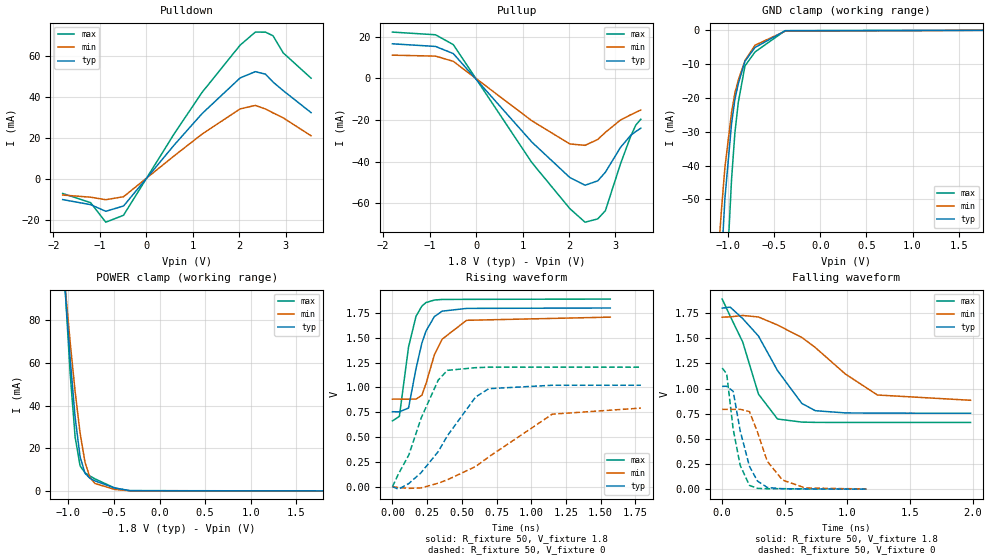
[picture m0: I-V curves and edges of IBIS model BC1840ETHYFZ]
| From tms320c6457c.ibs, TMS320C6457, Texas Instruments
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|   Model Cell BC1840ETHYFZ
[Model]   BC1840ETHYFZ
Model_type   I/O
Polarity   Non-Inverting
Enable   Active-Low
Vinl =  0.63
Vinh =  1.17
Cref =  15pF
Rref =  100.00M
Vref =  0V
Vmeas =  0.9
C_comp   1.349819p   1.120324p   1.692072p
[Model Spec]
Vinl   0.63   0.5985   0.6615
Vinh   1.17   1.1115   1.2285
[Temperature Range]   25   125   -40
[Voltage Range]   1.8   1.71   1.89
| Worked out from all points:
|   slope of the pulldown table from 0 to 0.27 V, typ, clamps not added: 35.3 ohm
|   slope of the pullup table from 0 to 0.27 V, typ, clamps not added: 37.2 ohm
|   GND clamp passes 1 mA (typ) near -0.49 V on its own axis
|   POWER clamp passes 1 mA (typ) near -0.46 V on its own axis
|   rising waveform, R_fixture 50, V_fixture 1.8: 20-80 % time 106ps typ, 144ps min, 82.5ps max; typ from 0.755 V to 1.8 V
|   rising waveform, R_fixture 50, V_fixture 0: 20-80 % time 301ps typ, 481ps min, 204ps max; typ from 0 V to 1.02 V
|   falling waveform, R_fixture 50, V_fixture 1.8: 20-80 % time 318ps typ, 511ps min, 210ps max; typ from 1.8 V to 0.755 V
|   falling waveform, R_fixture 50, V_fixture 0: 20-80 % time 111ps typ, 155ps min, 87.7ps max; typ from 1.02 V to 0.001 V
[POWER_clamp]
|   voltage   I(typ)   I(min)   I(max)
-1.8V     632.8mA    511.6mA    764.8mA
-1.055V   105.4mA    104.1mA    108.4mA
-1.036V   93.87mA    95.15mA    94.04mA
-981.8mV  61.86mA    69.76mA    55.16mA
-927.3mV  34.54mA    46.61mA    25.28mA
-872.7mV  15.98mA    27.11mA    11.74mA
-818.2mV  8.247mA    13.33mA    8.475mA
-763.6mV  5.887mA    6.222mA    6.958mA
-709.1mV  4.698mA    3.474mA    5.639mA
-490.9mV  1.354mA    698.9uA    1.342mA
-327.3mV  148.4uA    55.01uA    101.1uA
1.8V      1.91nA     90.78nA    1.181nA
[Pulldown]
|   voltage   I(typ)   I(min)   I(max)
-1.8V     -9.975mA   -7.741mA   -6.98mA
-1.2V     -12.44mA   -8.799mA   -11.46mA
-872.7mV  -15.69mA   -10.03mA   -21.01mA
-490.9mV  -13.1mA    -8.569mA   -17.62mA
600mV     16.72mA    11.42mA    22.21mA
1.2V      32.04mA    22.03mA    42.42mA
2.018V    49.45mA    34.33mA    65.47mA
2.345V    52.52mA    36.03mA    71.85mA
2.564V    51.3mA     34.29mA    71.83mA
2.727V    47.43mA    32.37mA    70.04mA
2.945V    43.27mA    29.96mA    61.7mA
3.545V    32.51mA    21.19mA    49.34mA
[Pullup]
|   voltage   I(typ)   I(min)   I(max)
-1.8V     16.61mA    11.16mA    22.24mA
-872.7mV  15.35mA    10.7mA     20.95mA
-490.9mV  11.93mA    8.207mA    16.23mA
1.2V      -30.58mA   -20.35mA   -40.43mA
2.018V    -47.62mA   -31.49mA   -62.56mA
2.345V    -51.31mA   -32.14mA   -69.06mA
2.618V    -49.2mA    -29.35mA   -67.48mA
2.782V    -45.08mA   -25.92mA   -63.56mA
3.109V    -33.1mA    -19.97mA   -40.96mA
3.327V    -27.37mA   -17.47mA   -27.8mA
3.436V    -25.53mA   -16.32mA   -22.48mA
3.545V    -23.89mA   -15.19mA   -19.61mA
[GND_clamp]
|   voltage   I(typ)   I(min)   I(max)
-1.8V     -625.6mA   -431.7mA   -991.9mA
-1.145V   -111.9mA   -81.73mA   -187.7mA
-1.109V   -89.09mA   -66.77mA   -149.9mA
-1.073V   -68.4mA    -53.08mA   -115.1mA
-1.036V   -49.81mA   -40.66mA   -83.47mA
-963.6mV  -27.57mA   -24.26mA   -44.03mA
-927.3mV  -20.4mA    -18.51mA   -30.3mA
-890.9mV  -15.83mA   -14.79mA   -21.39mA
-818.2mV  -9.128mA   -8.959mA   -10.52mA
-709.1mV  -5.065mA   -4.407mA   -6.394mA
-381.8mV  -133.5uA   -250.9uA   -83.03uA
1.764V    525.5pA    131nA      211pA
[Ramp]
| variable   typ   min   max
dV/dt_f  0.6424274/0.3293562n   0.509031/0.5327809n  0.7545297/0.2171174n
dV/dt_r  0.6288352/0.3128308n  0.4883315/0.5013298n  0.7405774/0.21202n
R_load = 50
[Rising Waveform]
R_fixture = 50
V_fixture = 1.8
V_fixture_min = 1.71
V_fixture_max = 1.89
|   time   V(typ)   V(min)   V(max)
0s        755.2mV    882.1mV    663.1mV
50ps      754.3mV    882.1mV    708.2mV
116ps     792.6mV    881.9mV    1.407V
170ps     1.19V      882.6mV    1.717V
212ps     1.446V     921.1mV    1.819V
242ps     1.568V     1.039V     1.855V
302ps     1.713V     1.327V     1.88V
358ps     1.768V     1.486V     1.886V
534ps     1.796V     1.676V     1.887V
1.57ns    1.8V       1.708V     1.89V
[Rising Waveform]
R_fixture = 50
V_fixture = 0
V_fixture_min = 0
V_fixture_max = 0
|   time   V(typ)   V(min)   V(max)
0s        88.36nV    176nV      31.28nV
44ps      -24.59mV   -7.139mV   130.6mV
118ps     31.98mV    -16.45mV   320mV
206ps     140.5mV    -11.95mV   688.5mV
330ps     353.8mV    35.61mV    1.074V
396ps     513.4mV    69.67mV    1.172V
600ps     904.5mV    203.8mV    1.199V
694ps     987.5mV    300.5mV    1.204V
1.152ns   1.022V     730.9mV    1.204V
1.79ns    1.022V     791.8mV    1.204V
[Falling Waveform]
R_fixture = 50
V_fixture = 1.8
V_fixture_min = 1.71
V_fixture_max = 1.89
|   time   V(typ)   V(min)   V(max)
0s        1.8V       1.71V      1.89V
64ps      1.81V      1.713V     1.72V
164ps     1.696V     1.727V     1.463V
290ps     1.522V     1.712V     944.6mV
442ps     1.179V     1.632V     697.4mV
636ps     852.7mV    1.508V     666.9mV
744ps     780mV      1.408V     664mV
984ps     758.2mV    1.145V     663.2mV
1.24ns    755.6mV    936.2mV    663.1mV
1.984ns   755.2mV    883.8mV    663.1mV
[Falling Waveform]
R_fixture = 50
V_fixture = 0
V_fixture_min = 0
V_fixture_max = 0
|   time   V(typ)   V(min)   V(max)
0s        1.022V     793.5mV    1.204V
36ps      1.023V     793.5mV    1.147V
88ps      972.3mV    793.5mV    594.9mV
144ps     579.8mV    794mV      236.3mV
218ps     226.5mV    771.5mV    37.12mV
282ps     80.7mV     568.1mV    7.818mV
360ps     17.06mV    277.6mV    4.059mV
482ps     3.902mV    90.58mV    4.92mV
664ps     2.308mV    12.01mV    2.412mV
1.152ns   1.265mV    1.72mV     56.76uV
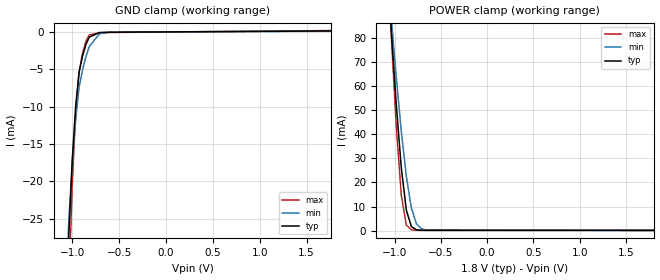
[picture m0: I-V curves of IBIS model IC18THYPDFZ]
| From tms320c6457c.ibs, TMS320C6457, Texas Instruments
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|   Model Cell IC18THYPDFZ
[Model]   IC18THYPDFZ
Model_type   Input
Polarity   Non-Inverting
|Cell operated at 1.8(nom)
|BUFFER OPERATING IN WEAK PULLDOWN MODE
|WITH +/- 5% VDDS
Vinl =  0.63
Vinh =  1.17
C_comp   0.7118224p   0.6228336p   0.8322228p
[Model Spec]
Vinl   0.63   0.5985   0.6615
Vinh   1.17   1.1115   1.2285
[Temperature Range]   25   125   -40
[Voltage Range]   1.8   1.71   1.89
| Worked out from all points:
|   GND clamp passes 1 mA (typ) near -0.83 V on its own axis
|   POWER clamp passes 1 mA (typ) near -0.79 V on its own axis
[POWER_clamp]
|   voltage   I(typ)   I(min)   I(max)
-1.8V     607.1mA    492.9mA    733.7mA
-1.055V   94.83mA    97.26mA    95.27mA
-1.036V   83.65mA    88.56mA    81.36mA
-981.8mV  52.59mA    63.87mA    43.61mA
-927.3mV  26.18mA    41.38mA    14.77mA
-872.7mV  8.488mA    22.52mA    2.281mA
-818.2mV  1.679mA    9.367mA    329.5uA
-763.6mV  320.4uA    2.879mA    161.9uA
-709.1mV  122uA      754.7uA    149.4uA
-654.5mV  95.78uA    214.5uA    148.3uA
1.8V      90.13uA    54.48uA    145.3uA
[GND_clamp]
|   voltage   I(typ)   I(min)   I(max)
-1.8V     -542mA     -381.8mA   -757.7mA
-1.073V   -42.86mA   -36.02mA   -57.35mA
-1.036V   -26.92mA   -25.12mA   -33.88mA
-1V       -17.11mA   -17.6mA    -20.43mA
-963.6mV  -9.945mA   -11.71mA   -10.93mA
-927.3mV  -5.429mA   -7.442mA   -5.388mA
-890.9mV  -3.287mA   -5.15mA    -2.922mA
-854.5mV  -1.723mA   -3.324mA   -1.27mA
-818.2mV  -734.7uA   -1.966mA   -430.8uA
-709.1mV  -120uA     -294.3uA   -144.9uA
-600mV    -81.62uA   -67.48uA   -118.2uA
1.764V    90uA       54.59uA    144.6uA
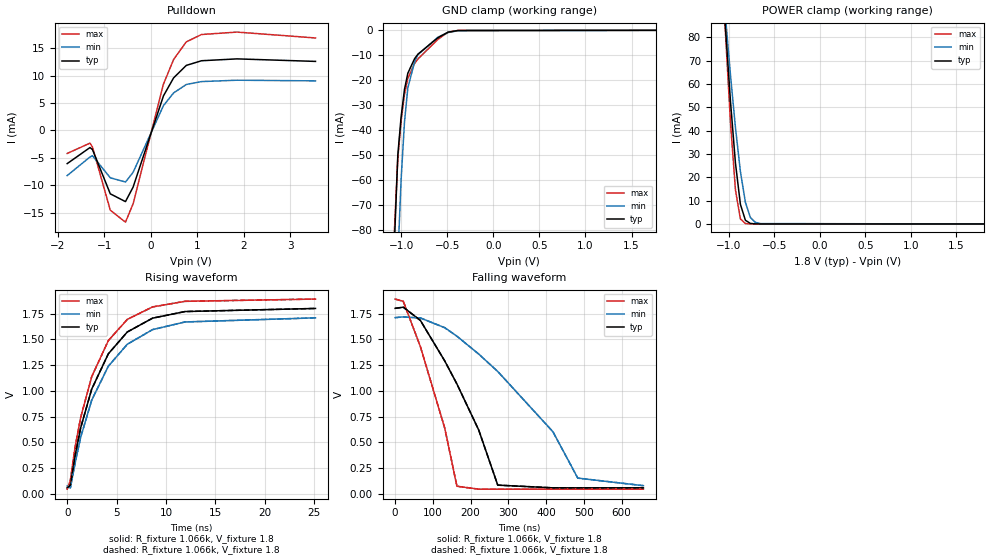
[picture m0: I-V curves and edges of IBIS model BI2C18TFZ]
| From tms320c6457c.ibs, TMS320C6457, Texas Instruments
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|   Model Cell BI2C18TFZ
|BI2C18TFZ_1P8
[Model]   BI2C18TFZ
Model_type   I/O_open_drain
Polarity   Non-Inverting
Enable   Active-Low
|Cell operated at 1.8(nom)
|BUFFER WITH +/- 5% VDDS
Vinl =  0.54
Vinh =  1.26
Cref =  400pF
Rref =  528
Vref =  1.8V
Vmeas =  0.9
C_comp   2.200517p   2.105009p   2.204653p
[Model Spec]
Vinl   0.54   0.513   0.567
Vinh   1.26   1.197   1.323
[Temperature Range]   25   125   -40
[Voltage Range]   1.8   1.71   1.89
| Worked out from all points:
|   slope of the pulldown table from 0 to 0.27 V, typ, clamps not added: 43.2 ohm
|   GND clamp passes 1 mA (typ) near -0.51 V on its own axis
|   POWER clamp passes 1 mA (typ) near -0.79 V on its own axis
|   rising waveform, R_fixture 1.066k, V_fixture 1.8: 20-80 % time 3.98ns typ, 4.3ns min, 3.66ns max; typ from 0.06 V to 1.8 V
|   rising waveform, R_fixture 1.066k, V_fixture 1.8: 20-80 % time 3.98ns typ, 4.3ns min, 3.66ns max; typ from 0.06 V to 1.8 V
|   falling waveform, R_fixture 1.066k, V_fixture 1.8: 20-80 % time 134ns typ, 236ns min, 86.2ns max; typ from 1.8 V to 0.06 V
|   falling waveform, R_fixture 1.066k, V_fixture 1.8: 20-80 % time 134ns typ, 236ns min, 86.2ns max; typ from 1.8 V to 0.06 V
[POWER_clamp]
|   voltage   I(typ)   I(min)   I(max)
-1.8V     607mA      492.8mA    733.6mA
-1.055V   94.75mA    97.21mA    95.13mA
-1.036V   83.56mA    88.51mA    81.22mA
-981.8mV  52.51mA    63.81mA    43.47mA
-927.3mV  26.09mA    41.33mA    14.63mA
-872.7mV  8.398mA    22.47mA    2.133mA
-818.2mV  1.587mA    9.312mA    180.9uA
-763.6mV  228.3uA    2.824mA    13.44uA
-709.1mV  29.99uA    699.2uA    1.06uA
-654.5mV  3.859uA    159uA      146.5nA
1.8V      1.028nA    44.53nA    569.6pA
[Pulldown]
|   voltage   I(typ)   I(min)   I(max)
-1.8V     -6.04mA    -8.214mA   -4.186mA
-1.309V   -3.11mA    -4.831mA   -2.309mA
-1.255V   -3.493mA   -4.611mA   -3.032mA
-872.7mV  -11.54mA   -8.621mA   -14.52mA
-545.5mV  -12.96mA   -9.39mA    -16.71mA
-381.8mV  -10.33mA   -7.634mA   -13.37mA
272.7mV   6.31mA     4.531mA    8.464mA
490.9mV   9.582mA    6.839mA    12.93mA
763.6mV   11.85mA    8.375mA    16.14mA
1.091V    12.7mA     8.903mA    17.48mA
1.855V    13.04mA    9.156mA    17.92mA
3.545V    12.58mA    9.032mA    16.85mA
[GND_clamp]
|   voltage   I(typ)   I(min)   I(max)
-1.8V     -4.55A     -4.415A    -4.715A
-1.073V   -85.44mA   -159.9mA   -80.66mA
-1.036V   -50.11mA   -91.94mA   -51.37mA
-1V       -34.68mA   -59.8mA    -36.45mA
-963.6mV  -23.72mA   -36.86mA   -25.76mA
-927.3mV  -17.22mA   -23.12mA   -19.3mA
-854.5mV  -11.44mA   -12.73mA   -13.33mA
-818.2mV  -9.595mA   -9.796mA   -11.52mA
-600mV    -2.95mA    -2.738mA   -3.602mA
-490.9mV  -739.5uA   -891.5uA   -763.3uA
-381.8mV  -69.49uA   -145.4uA   -41.6uA
1.764V    959.8pA    46.51nA    169.7pA
[Ramp]
| variable   typ   min   max
dV/dt_f   1.051879/0.1358345u  0.9823889/0.2380683u   1.118592/87.62096n
dV/dt_r  0.1590767/0.3489175n   0.121841/0.5578951n  0.1864863/0.251782n
R_load = 1.066k
[Rising Waveform]
R_fixture = 1.066k
V_fixture = 1.8
V_fixture_min = 1.71
V_fixture_max = 1.89
|   time   V(typ)   V(min)   V(max)
0s        60.28mV    79.47mV    47.35mV
320ps     83.48mV    60.28mV    131.3mV
800ps     373mV      299.4mV    455.6mV
1.36ns    640.9mV    549.7mV    740.3mV
2.48ns    1.017V     910.1mV    1.138V
4.16ns    1.359V     1.239V     1.487V
6.08ns    1.571V     1.452V     1.693V
8.64ns    1.705V     1.594V     1.814V
11.92ns   1.769V     1.668V     1.868V
25.12ns   1.799V     1.708V     1.89V
[Rising Waveform]
R_fixture = 1.066k
V_fixture = 1.8
V_fixture_min = 1.71
V_fixture_max = 1.89
|   time   V(typ)   V(min)   V(max)
0s        60.28mV    79.47mV    47.35mV
320ps     83.48mV    60.28mV    131.3mV
800ps     373mV      299.4mV    455.6mV
1.36ns    640.9mV    549.7mV    740.3mV
2.48ns    1.017V     910.1mV    1.138V
4.16ns    1.359V     1.239V     1.487V
6.08ns    1.571V     1.452V     1.693V
8.64ns    1.705V     1.594V     1.814V
11.92ns   1.769V     1.668V     1.868V
25.12ns   1.799V     1.708V     1.89V
[Falling Waveform]
R_fixture = 1.066k
V_fixture = 1.8
V_fixture_min = 1.71
V_fixture_max = 1.89
|   time   V(typ)   V(min)   V(max)
0s        1.8V       1.71V      1.89V
21.68ns   1.811V     1.717V     1.868V
66.96ns   1.683V     1.707V     1.429V
131.7ns   1.289V     1.612V     636.7mV
163.8ns   1.067V     1.53V      75.51mV
221.5ns   621.3mV    1.357V     47.7mV
272ns     86.4mV     1.188V     47.36mV
418.1ns   60.32mV    604.4mV    47.35mV
484.1ns   60.28mV    154.5mV    47.35mV
658ns     60.28mV    81.19mV    47.35mV
[Falling Waveform]
R_fixture = 1.066k
V_fixture = 1.8
V_fixture_min = 1.71
V_fixture_max = 1.89
|   time   V(typ)   V(min)   V(max)
0s        1.8V       1.71V      1.89V
21.68ns   1.811V     1.717V     1.868V
66.96ns   1.683V     1.707V     1.429V
131.7ns   1.289V     1.612V     636.7mV
163.8ns   1.067V     1.53V      75.51mV
221.5ns   621.3mV    1.357V     47.7mV
272ns     86.4mV     1.188V     47.36mV
418.1ns   60.32mV    604.4mV    47.35mV
484.1ns   60.28mV    154.5mV    47.35mV
658ns     60.28mV    81.19mV    47.35mV
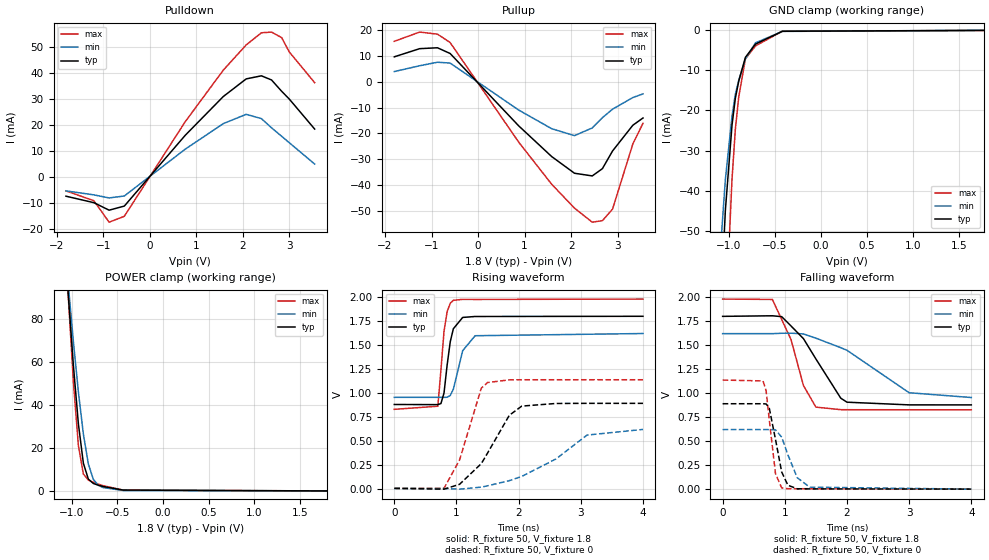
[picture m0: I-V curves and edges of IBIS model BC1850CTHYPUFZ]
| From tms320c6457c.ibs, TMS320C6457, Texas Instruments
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|   Model Cell BC1850CTHYPUFZ
[Model]   BC1850CTHYPUFZ
Model_type   I/O
Polarity   Non-Inverting
Enable   Active-Low
|Cell operated at 1.8(nom) PULLUP_ON
Vinl =  0.63
Vinh =  1.17
Cref =  15.0000pF
Rref =  100.0000M
Vref =  0V
Vmeas =  0.9
C_comp   1.238561p   1.006605p   1.548795p
[Model Spec]
Vinl   0.63   0.567   0.693
Vinh   1.17   1.053   1.287
[Temperature Range]   25   125   -40
[Voltage Range]   1.8   1.62   1.98
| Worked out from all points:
|   slope of the pulldown table from 0 to 0.27 V, typ, clamps not added: 45.7 ohm
|   slope of the pullup table from 0 to 0.27 V, typ, clamps not added: 49.4 ohm
|   GND clamp passes 1 mA (typ) near -0.54 V on its own axis
|   POWER clamp passes 1 mA (typ) near -0.54 V on its own axis
|   rising waveform, R_fixture 50, V_fixture 1.8: 20-80 % time 119ps typ, 164ps min, 99.4ps max; typ from 0.878 V to 1.8 V
|   rising waveform, R_fixture 50, V_fixture 0: 20-80 % time 501ps typ, 891ps min, 328ps max; typ from 0.002 V to 0.891 V
|   falling waveform, R_fixture 50, V_fixture 1.8: 20-80 % time 559ps typ, 964ps min, 355ps max; typ from 1.8 V to 0.878 V
|   falling waveform, R_fixture 50, V_fixture 0: 20-80 % time 147ps typ, 219ps min, 116ps max; typ from 0.891 V to 0.002 V
[POWER_clamp]
|   voltage   I(typ)   I(min)   I(max)
-1.8V     630.5mA    511.7mA    760.7mA
-1.055V   101.7mA    104mA      103.4mA
-1.036V   90.22mA    94.97mA    89.19mA
-981.8mV  58.34mA    69.43mA    50.65mA
-927.3mV  31.23mA    46.13mA    21.1mA
-872.7mV  12.92mA    26.49mA    7.883mA
-818.2mV  5.49mA     12.59mA    5.062mA
-763.6mV  3.485mA    5.395mA    4.02mA
-709.1mV  2.664mA    2.626mA    3.181mA
-654.5mV  2.059mA    1.546mA    2.418mA
-436.4mV  395.3uA    203.1uA    376.6uA
1.8V      143.9nA    121.3nA    204.6nA
[Pulldown]
|   voltage   I(typ)   I(min)   I(max)
-1.8V     -7.221mA   -5.188mA   -5.193mA
-1.2V     -9.719mA   -6.718mA   -8.96mA
-872.7mV  -12.6mA    -7.896mA   -17.22mA
-545.5mV  -11.02mA   -7.144mA   -14.95mA
763.6mV   16.19mA    10.86mA    21.42mA
1.582V    31.1mA     20.68mA    41.25mA
2.073V    37.87mA    24.25mA    50.93mA
2.4V      39.06mA    22.61mA    55.6mA
2.618V    37.47mA    19.08mA    55.87mA
2.836V    33.11mA    15.81mA    53.74mA
3V        30.12mA    13.33mA    48.23mA
3.545V    18.59mA    5.142mA    36.43mA
[Pullup]
|   voltage   I(typ)   I(min)   I(max)
-1.8V     9.587mA    3.896mA    15.57mA
-1.255V   12.73mA    6.137mA    19.13mA
-872.7mV  13.08mA    7.494mA    18.34mA
-600mV    10.87mA    7.175mA    15.09mA
872.7mV   -17.04mA   -10.95mA   -23.32mA
1.582V    -28.9mA    -18.15mA   -39.58mA
2.073V    -35.35mA   -20.84mA   -48.82mA
2.455V    -36.38mA   -17.86mA   -54.24mA
2.673V    -33.57mA   -13.9mA    -53.65mA
2.891V    -26.75mA   -10.62mA   -49.2mA
3.327V    -16.82mA   -6.13mA    -24.05mA
3.545V    -14.03mA   -4.729mA   -16.07mA
[GND_clamp]
|   voltage   I(typ)   I(min)   I(max)
-1.8V     -611mA     -422.9mA   -952.5mA
-1.145V   -105.8mA   -77.64mA   -174.4mA
-1.109V   -83.48mA   -62.94mA   -137.9mA
-1.073V   -63.23mA   -49.5mA    -104.5mA
-1.036V   -45.05mA   -37.34mA   -74.12mA
-963.6mV  -23.65mA   -21.44mA   -37.18mA
-927.3mV  -16.91mA   -15.94mA   -24.65mA
-890.9mV  -12.72mA   -12.46mA   -16.66mA
-818.2mV  -6.73mA    -7.089mA   -7.08mA
-709.1mV  -3.424mA   -3.104mA   -3.879mA
-418.2mV  -222.7uA   -258.8uA   -211.4uA
1.764V    -3.83uA    10.69uA    -32.86uA
[Ramp]
| variable   typ   min   max
dV/dt_f  0.5571886/0.5682756n  0.4021354/0.9788624n  0.6961114/0.355969n
dV/dt_r  0.5386391/0.5091701n  0.3743707/0.9070246n  0.6869947/0.3333883n
R_load = 50
[Rising Waveform]
R_fixture = 50
V_fixture = 1.8
V_fixture_min = 1.62
V_fixture_max = 1.98
| time   V(typ)   V(min)   V(max)
|   time   V(typ)   V(min)   V(max)
0s        878.5mV    953.3mV    827.8mV
700ps     877.2mV    953.3mV    860.4mV
750ps     888.1mV    953.3mV    1.236V
800ps     999.4mV    953.3mV    1.645V
850ps     1.291V     954.2mV    1.849V
900ps     1.534V     972.8mV    1.937V
950ps     1.67V      1.038V     1.967V
1.1ns     1.788V     1.441V     1.977V
1.3ns     1.798V     1.597V     1.976V
4ns       1.8V       1.62V      1.98V
[Rising Waveform]
R_fixture = 50
V_fixture = 0
V_fixture_min = 0
V_fixture_max = 0
| time   V(typ)   V(min)   V(max)
|   time   V(typ)   V(min)   V(max)
0s        2.104mV    1.267mV    2.952mV
800ps     -6.071mV   1.238mV    3.345mV
1.05ns    44.81mV    -5.819mV   299.4mV
1.4ns     261.1mV    15.29mV    1.05V
1.5ns     370.9mV    29mV       1.108V
1.85ns    766mV      82.91mV    1.136V
2.05ns    861.6mV    127.1mV    1.137V
2.6ns     889.2mV    309.4mV    1.137V
3.1ns     890.5mV    559.1mV    1.137V
4ns       890.6mV    618.1mV    1.137V
[Falling Waveform]
R_fixture = 50
V_fixture = 1.8
V_fixture_min = 1.62
V_fixture_max = 1.98
| time   V(typ)   V(min)   V(max)
|   time   V(typ)   V(min)   V(max)
0s        1.8V       1.62V      1.98V
800ps     1.806V     1.62V      1.976V
950ps     1.797V     1.624V     1.767V
1.1ns     1.7V       1.625V     1.559V
1.3ns     1.568V     1.617V     1.08V
1.5ns     1.357V     1.573V     855.4mV
1.9ns     948.7mV    1.474V     828.8mV
2ns       906.6mV    1.447V     828.3mV
3ns       878.7mV    1.005V     827.8mV
4ns       878.5mV    955.3mV    827.8mV
[Falling Waveform]
R_fixture = 50
V_fixture = 0
V_fixture_min = 0
V_fixture_max = 0
| time   V(typ)   V(min)   V(max)
|   time   V(typ)   V(min)   V(max)
0s        890.6mV    621.6mV    1.137V
650ps     890.5mV    621.6mV    1.128V
700ps     888.2mV    621.6mV    1.024V
750ps     845.8mV    621.6mV    725.7mV
850ps     520.3mV    618.1mV    163mV
950ps     180.1mV    543.4mV    14.5mV
1.05ns    42.34mV    358.6mV    6.493mV
1.2ns     5.458mV    120.9mV    5.551mV
1.4ns     4.378mV    22.39mV    6.681mV
4ns       2.104mV    1.424mV    2.952mV
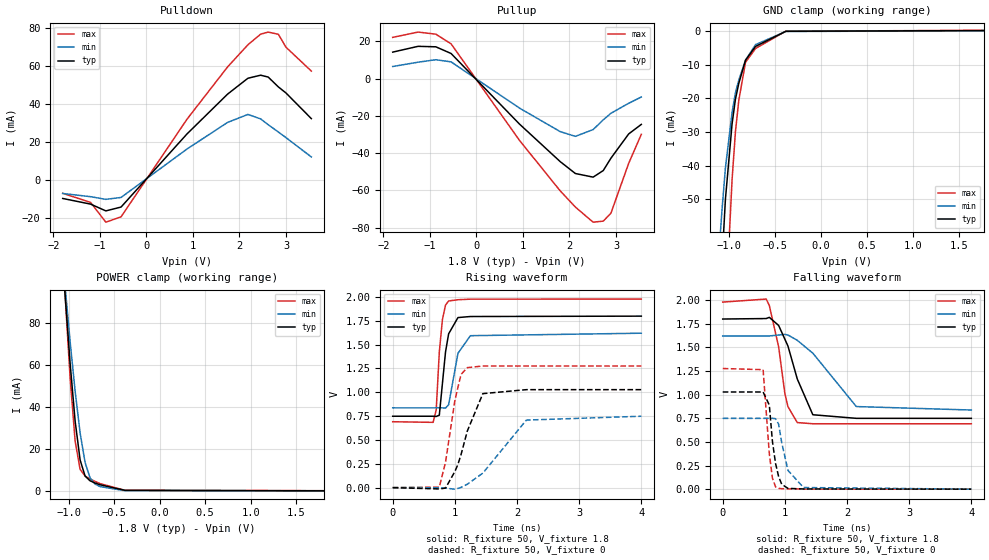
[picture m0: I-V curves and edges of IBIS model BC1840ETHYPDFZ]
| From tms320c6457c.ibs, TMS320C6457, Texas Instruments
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|   Model Cell BC1840ETHYPDFZ
[Model]   BC1840ETHYPDFZ
Model_type   I/O
Polarity   Non-Inverting
Enable   Active-Low
|Cell operated at 1.8(nom) PULLDOWN_ON
Vinl =  0.63
Vinh =  1.17
Cref =  15.0000pF
Rref =  100.0000M
Vref =  0V
Vmeas =  0.9
C_comp   1.426089p   1.180441p   1.7593p
[Model Spec]
Vinl   0.63   0.567   0.693
Vinh   1.17   1.053   1.287
[Temperature Range]   25   125   -40
[Voltage Range]   1.8   1.62   1.98
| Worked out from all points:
|   slope of the pulldown table from 0 to 0.27 V, typ, clamps not added: 34.9 ohm
|   slope of the pullup table from 0 to 0.27 V, typ, clamps not added: 36.8 ohm
|   GND clamp passes 1 mA (typ) near -0.51 V on its own axis
|   POWER clamp passes 1 mA (typ) near -0.49 V on its own axis
|   rising waveform, R_fixture 50, V_fixture 1.8: 20-80 % time 114ps typ, 154ps min, 82.7ps max; typ from 0.748 V to 1.8 V
|   rising waveform, R_fixture 50, V_fixture 0: 20-80 % time 297ps typ, 520ps min, 192ps max; typ from 0 V to 1.03 V
|   falling waveform, R_fixture 50, V_fixture 1.8: 20-80 % time 303ps typ, 551ps min, 196ps max; typ from 1.8 V to 0.748 V
|   falling waveform, R_fixture 50, V_fixture 0: 20-80 % time 115ps typ, 163ps min, 95.8ps max; typ from 1.03 V to 0 V
[POWER_clamp]
|   voltage   I(typ)   I(min)   I(max)
-1.8V     636mA      516.1mA    767.2mA
-1.055V   104.1mA    105.7mA    106.7mA
-1.036V   92.57mA    96.67mA    92.38mA
-981.8mV  60.55mA    70.95mA    53.56mA
-927.3mV  33.26mA    47.48mA    23.75mA
-872.7mV  14.76mA    27.67mA    10.28mA
-818.2mV  7.115mA    13.61mA    7.13mA
-763.6mV  4.87mA     6.257mA    5.757mA
-709.1mV  3.81mA     3.333mA    4.6mA
-654.5mV  2.979mA    2.104mA    3.538mA
-381.8mV  327.8uA    153.2uA    355uA
1.8V      92.41uA    43.92uA    172uA
[Pulldown]
|   voltage   I(typ)   I(min)   I(max)
-1.8V     -9.779mA   -7.153mA   -7.061mA
-1.2V     -12.76mA   -8.852mA   -11.88mA
-872.7mV  -16.32mA   -10.25mA   -22.27mA
-545.5mV  -14.3mA    -9.25mA    -19.44mA
872.7mV   24.19mA    16.25mA    31.94mA
1.745V    45.14mA    30.24mA    59.46mA
2.182V    53.49mA    34.45mA    71.09mA
2.455V    55.09mA    32.1mA     76.69mA
2.618V    54.11mA    29.03mA    77.78mA
2.836V    48.93mA    25.2mA     76.62mA
3V        45.74mA    22.24mA    69.82mA
3.545V    32.25mA    12.07mA    57.27mA
[Pullup]
|   voltage   I(typ)   I(min)   I(max)
-1.8V     14.18mA    6.455mA    22.1mA
-1.255V   17.29mA    8.777mA    24.93mA
-872.7mV  17.03mA    10.1mA     23.81mA
-545.5mV  13.45mA    8.957mA    18.63mA
927.3mV   -24.47mA   -15.88mA   -33.23mA
1.8V      -44.55mA   -28.46mA   -60.23mA
2.127V    -50.96mA   -31.02mA   -68.96mA
2.509V    -52.9mA    -27.38mA   -77.08mA
2.727V    -49.37mA   -22.15mA   -76.5mA
2.891V    -42.76mA   -18.64mA   -72.28mA
3.273V    -29.73mA   -13.28mA   -45.52mA
3.545V    -24.6mA    -9.876mA   -29.93mA
[GND_clamp]
|   voltage   I(typ)   I(min)   I(max)
-1.8V     -628.6mA   -433.5mA   -1A
-1.145V   -112.5mA   -82mA      -189.7mA
-1.109V   -89.59mA   -66.97mA   -151.5mA
-1.073V   -68.78mA   -53.22mA   -116.4mA
-1.036V   -50.06mA   -40.74mA   -84.39mA
-963.6mV  -27.57mA   -24.21mA   -44.13mA
-927.3mV  -20.28mA   -18.4mA    -29.96mA
-890.9mV  -15.59mA   -14.63mA   -20.66mA
-818.2mV  -8.712mA   -8.693mA   -9.349mA
-709.1mV  -4.606mA   -4.075mA   -5.223mA
-381.8mV  -119uA     -183.5uA   -100.5uA
1.764V    92.34uA    44.74uA    171.3uA
[Ramp]
| variable   typ   min   max
dV/dt_f  0.6452481/0.3139694n  0.4807723/0.5727689n  0.7909033/0.1986962n
dV/dt_r  0.6301307/0.3060858n  0.4598002/0.5397013n  0.7809861/0.198104n
R_load = 50
[Rising Waveform]
R_fixture = 50
V_fixture = 1.8
V_fixture_min = 1.62
V_fixture_max = 1.98
| time   V(typ)   V(min)   V(max)
|   time   V(typ)   V(min)   V(max)
0s        748.5mV    836.3mV    690.8mV
650ps     748.5mV    836.3mV    684.3mV
700ps     746.2mV    836.3mV    814.6mV
750ps     759.5mV    836.4mV    1.423V
800ps     1.093V     836.3mV    1.763V
850ps     1.424V     834.3mV    1.914V
900ps     1.613V     869.3mV    1.957V
1.05ns    1.783V     1.409V     1.97V
1.25ns    1.794V     1.593V     1.976V
4ns       1.798V     1.619V     1.977V
[Rising Waveform]
R_fixture = 50
V_fixture = 0
V_fixture_min = 0
V_fixture_max = 0
| time   V(typ)   V(min)   V(max)
|   time   V(typ)   V(min)   V(max)
0s        630.5nV    578nV      738.7nV
750ps     -13.98mV   59.29uV    5.219mV
850ps     -5.002mV   -5.747mV   266.1mV
1ns       168.5mV    -16.27mV   912.3mV
1.05ns    244.6mV    -8.61mV    1.053V
1.1ns     348mV      2.53mV     1.187V
1.2ns     592.6mV    35.2mV     1.258V
1.45ns    985.4mV    151.7mV    1.275V
2.15ns    1.027V     708.1mV    1.275V
4ns       1.027V     748.3mV    1.275V
[Falling Waveform]
R_fixture = 50
V_fixture = 1.8
V_fixture_min = 1.62
V_fixture_max = 1.98
| time   V(typ)   V(min)   V(max)
|   time   V(typ)   V(min)   V(max)
0s        1.798V     1.619V     1.977V
700ps     1.803V     1.619V     2.009V
750ps     1.816V     1.619V     1.941V
900ps     1.73V      1.629V     1.503V
1ns       1.585V     1.636V     1.012V
1.05ns    1.512V     1.629V     871.2mV
1.2ns     1.164V     1.573V     703.8mV
1.45ns    786.4mV    1.437V     691.4mV
2.15ns    748.6mV    873mV      690.8mV
4ns       748.5mV    836.3mV    690.8mV
[Falling Waveform]
R_fixture = 50
V_fixture = 0
V_fixture_min = 0
V_fixture_max = 0
| time   V(typ)   V(min)   V(max)
|   time   V(typ)   V(min)   V(max)
0s        1.027V     748.3mV    1.275V
650ps     1.027V     748.3mV    1.263V
750ps     888.1mV    748.3mV    373mV
800ps     504.8mV    748.9mV    116.7mV
850ps     273mV      744.8mV    24.52mV
900ps     132mV      686.6mV    8.644mV
950ps     51.15mV    490.7mV    5.394mV
1.05ns    8.336mV    198.5mV    3.252mV
1.3ns     2.355mV    17.27mV    1.746mV
4ns       632.9nV    2.438uV    738.5nV
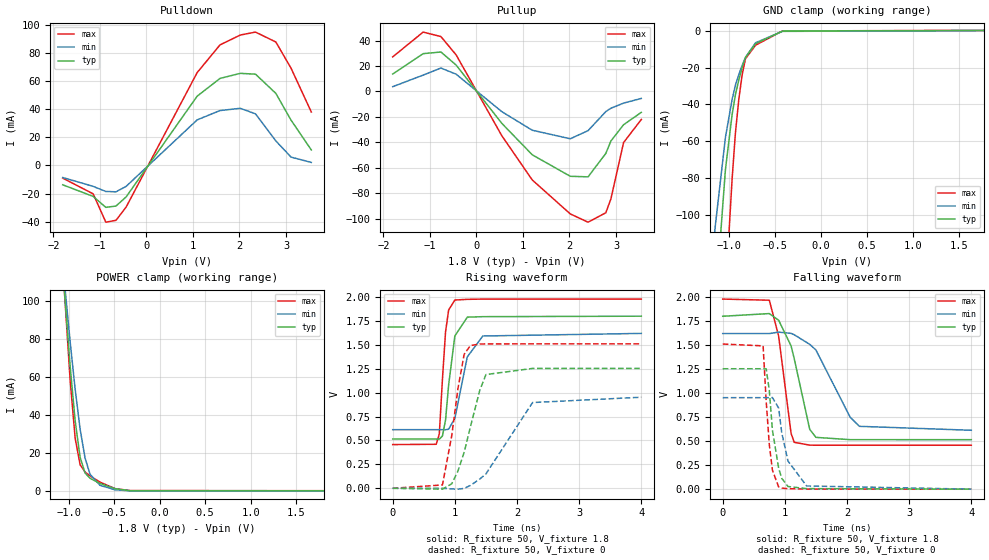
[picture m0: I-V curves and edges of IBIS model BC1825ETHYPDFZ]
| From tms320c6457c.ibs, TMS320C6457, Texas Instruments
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|   Model Cell BC1825ETHYPDFZ
[Model]   BC1825ETHYPDFZ
Model_type   I/O
Polarity   Non-Inverting
Enable   Active-Low
|Cell operated at 1.8(nom) PULLDOWN_ON
Vinl =  0.63
Vinh =  1.17
Cref =  15.0000pF
Rref =  100.0000M
Vref =  0V
Vmeas =  0.9
C_comp   1.831476p   1.400069p   2.413811p
[Model Spec]
Vinl   0.63   0.567   0.693
Vinh   1.17   1.053   1.287
[Temperature Range]   25   125   -40
[Voltage Range]   1.8   1.62   1.98
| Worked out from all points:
|   slope of the pulldown table from 0 to 0.27 V, typ, clamps not added: 19.6 ohm
|   slope of the pullup table from 0 to 0.27 V, typ, clamps not added: 21.2 ohm
|   GND clamp passes 1 mA (typ) near -0.50 V on its own axis
|   POWER clamp passes 1 mA (typ) near -0.47 V on its own axis
|   rising waveform, R_fixture 50, V_fixture 1.8: 20-80 % time 129ps typ, 202ps min, 91.8ps max; typ from 0.515 V to 1.8 V
|   rising waveform, R_fixture 50, V_fixture 0: 20-80 % time 301ps typ, 522ps min, 201ps max; typ from 0 V to 1.25 V
|   falling waveform, R_fixture 50, V_fixture 1.8: 20-80 % time 278ps typ, 471ps min, 195ps max; typ from 1.8 V to 0.515 V
|   falling waveform, R_fixture 50, V_fixture 0: 20-80 % time 137ps typ, 202ps min, 106ps max; typ from 1.25 V to 0 V
[POWER_clamp]
|   voltage   I(typ)   I(min)   I(max)
-1.8V     671.9mA    545.1mA    808.4mA
-1.073V   123.8mA    124.6mA    127.3mA
-1.055V   111.6mA    115.1mA    112.6mA
-981.8mV  65.69mA    78.5mA     58.31mA
-927.3mV  37.1mA     53.69mA    27.88mA
-872.7mV  17.74mA    32.6mA     13.81mA
-818.2mV  9.467mA    17.32mA    9.996mA
-763.6mV  6.699mA    8.818mA    7.978mA
-654.5mV  3.957mA    2.986mA    4.662mA
-490.9mV  1.244mA    666.5uA    1.282mA
-327.3mV  178.3uA    84.66uA    226.6uA
1.8V      92.42uA    43.92uA    172.1uA
[Pulldown]
|   voltage   I(typ)   I(min)   I(max)
-1.8V     -13.79mA   -8.604mA   -9.048mA
-1.145V   -22.06mA   -14.91mA   -20.23mA
-872.7mV  -29.85mA   -18.55mA   -40.39mA
-654.5mV  -28.9mA    -18.77mA   -39.05mA
-436.4mV  -22.41mA   -14.91mA   -29.64mA
1.091V    49.25mA    32.39mA    66.03mA
1.582V    61.86mA    39.02mA    85.71mA
2.018V    65.47mA    40.6mA     92.73mA
2.345V    64.89mA    36.67mA    94.82mA
2.782V    51.24mA    17.42mA    87.77mA
3.109V    32.2mA     5.915mA    69.14mA
3.545V    10.99mA    2.102mA    37.97mA
[Pullup]
|   voltage   I(typ)   I(min)   I(max)
-1.8V     13.68mA    3.76mA     27.17mA
-1.145V   29.68mA    12.85mA    46.61mA
-763.6mV  30.98mA    18.39mA    43.08mA
-436.4mV  20.7mA     13.56mA    28.7mA
545.5mV   -25mA      -15.84mA   -34.72mA
1.2V      -49.7mA    -30.43mA   -69.45mA
2.018V    -66.57mA   -37.11mA   -96.11mA
2.4V      -67.01mA   -30.75mA   -102.6mA
2.782V    -48.62mA   -15.78mA   -95.18mA
2.891V    -38.89mA   -13.16mA   -84.32mA
3.164V    -26.07mA   -9.131mA   -40.05mA
3.545V    -16.39mA   -5.462mA   -21.97mA
[GND_clamp]
|   voltage   I(typ)   I(min)   I(max)
-1.8V     -736.6mA   -498.6mA   -1.298A
-1.218V   -208mA     -143.8mA   -387.4mA
-1.145V   -149mA     -105.5mA   -281.3mA
-1.036V   -75.39mA   -57.91mA   -143mA
-963.6mV  -45.61mA   -37.33mA   -80.57mA
-927.3mV  -34.69mA   -29.52mA   -55.36mA
-890.9mV  -26.73mA   -23.84mA   -37.29mA
-854.5mV  -20.01mA   -18.83mA   -23.9mA
-818.2mV  -14.52mA   -14.47mA   -15.17mA
-709.1mV  -7.08mA    -6.549mA   -7.891mA
-418.2mV  -273.2uA   -398uA     -187.9uA
1.764V    92.35uA    44.78uA    171.3uA
[Ramp]
| variable   typ   min   max
dV/dt_f  0.7900843/0.288387n   0.6183598/0.4888713n  0.9377222/0.2020498n
dV/dt_r  0.7574561/0.3034474n  0.5763372/0.5282563n  0.9121567/0.2032812n
R_load = 50
[Rising Waveform]
R_fixture = 50
V_fixture = 1.8
V_fixture_min = 1.62
V_fixture_max = 1.98
| time   V(typ)   V(min)   V(max)
|   time   V(typ)   V(min)   V(max)
0s        514.9mV    612.8mV    457mV
700ps     514.7mV    612.8mV    460.1mV
750ps     514.3mV    612.8mV    568.5mV
800ps     546.9mV    613.1mV    1.138V
850ps     713.3mV    612.1mV    1.634V
900ps     1.082V     617.7mV    1.864V
1ns       1.593V     731.3mV    1.968V
1.2ns     1.789V     1.373V     1.975V
1.45ns    1.794V     1.592V     1.978V
4ns       1.799V     1.619V     1.978V
[Rising Waveform]
R_fixture = 50
V_fixture = 0
V_fixture_min = 0
V_fixture_max = 0
| time   V(typ)   V(min)   V(max)
|   time   V(typ)   V(min)   V(max)
0s        770.7nV    748.2nV    869.8nV
800ps     -9.054mV   336.5uV    34.93mV
950ps     47.68mV    -7.126mV   550.3mV
1.05ns    180.6mV    -8.273mV   1.044V
1.15ns    377.5mV    -1.643mV   1.401V
1.25ns    641.8mV    30.27mV    1.492V
1.4ns     1.022V     95.99mV    1.508V
1.5ns     1.189V     150.5mV    1.509V
2.25ns    1.253V     896.3mV    1.51V
4ns       1.253V     951.9mV    1.51V
[Falling Waveform]
R_fixture = 50
V_fixture = 1.8
V_fixture_min = 1.62
V_fixture_max = 1.98
| time   V(typ)   V(min)   V(max)
|   time   V(typ)   V(min)   V(max)
0s        1.799V     1.619V     1.978V
750ps     1.827V     1.619V     1.966V
900ps     1.758V     1.634V     1.593V
1.1ns     1.491V     1.621V     581.1mV
1.15ns    1.36V      1.607V     487.6mV
1.4ns     622.4mV    1.507V     458.1mV
1.5ns     538.9mV    1.448V     457.3mV
2.05ns    515.1mV    749.3mV    457mV
2.2ns     515mV      653.8mV    457mV
4ns       514.9mV    612.8mV    457mV
[Falling Waveform]
R_fixture = 50
V_fixture = 0
V_fixture_min = 0
V_fixture_max = 0
| time   V(typ)   V(min)   V(max)
|   time   V(typ)   V(min)   V(max)
0s        1.253V     951.9mV    1.51V
650ps     1.253V     951.9mV    1.491V
700ps     1.251V     951.9mV    910mV
750ps     1.026V     951.8mV    461.5mV
800ps     613.7mV    953.2mV    197.2mV
900ps     218mV      844.5mV    23.28mV
950ps     113mV      586.7mV    11.28mV
1.05ns    27.63mV    293.4mV    5.272mV
1.35ns    5.678mV    33.32mV    1.053mV
4ns       772.5nV    2.388uV    869.4nV
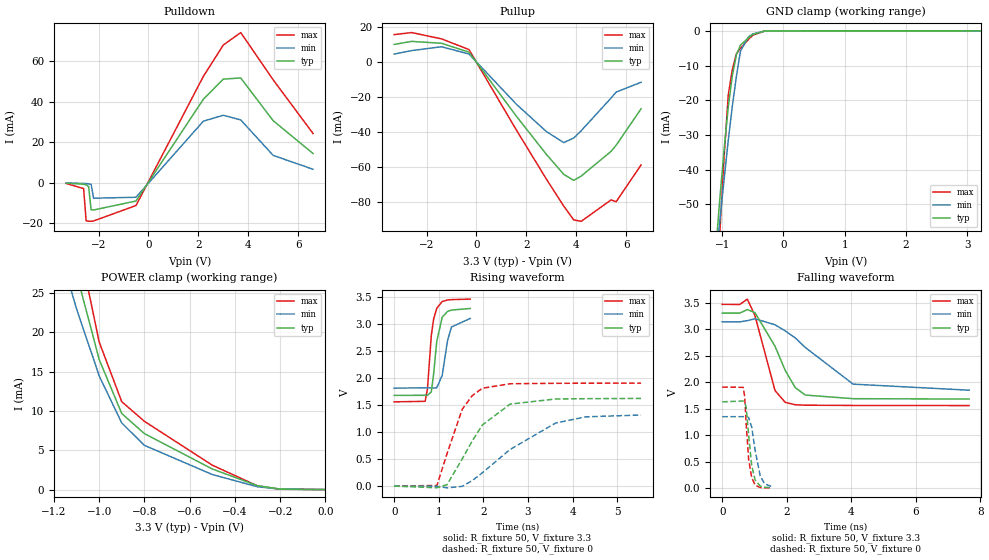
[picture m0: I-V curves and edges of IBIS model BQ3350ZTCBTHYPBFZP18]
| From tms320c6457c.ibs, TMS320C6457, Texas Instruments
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|   Model Cell BQ3350ZTCBTHYPBFZP18
[Model]   BQ3350ZTCBTHYPBFZP18
Model_type   I/O
Polarity   Non-Inverting
Enable   Active-Low
|Cell operated at 3.3(nom)  +/- 5% VDDS range IN NORMAL MODE with
|WEAK PULLUP and PULLDOWN OFF
Vinl =  0.8V
Vinh =  2V
Cref =  15pF
Rref =  100.00M
Vref =  0V
Vmeas =  1.65
C_comp   1.398066p   1.316554p   1.4907p
[Model Spec]
Vinl   0.8V   0.8V   0.8V
Vinh   2V   2V   2V
[Temperature Range]   25   125   -40
[Voltage Range]   3.3   3.135   3.465
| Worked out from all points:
|   slope of the pulldown table from 0 to 0.495 V, typ, clamps not added: 49.9 ohm
|   slope of the pullup table from 0 to 0.495 V, typ, clamps not added: 50.6 ohm
|   GND clamp passes 1 mA (typ) near -0.49 V on its own axis
|   POWER clamp passes 1 mA (typ) near -0.35 V on its own axis
|   rising waveform, R_fixture 50, V_fixture 3.3: 20-80 % time 137ps typ, 161ps min, 125ps max; typ from 1.68 V to 3.29 V
|   rising waveform, R_fixture 50, V_fixture 0: 20-80 % time 773ps typ, 1.31ns min, 496ps max; typ from 0 V to 1.62 V
|   falling waveform, R_fixture 50, V_fixture 3.3: 20-80 % time 755ps typ, 1.44ns min, 491ps max; typ from 3.3 V to 1.68 V
|   falling waveform, R_fixture 50, V_fixture 0: 20-80 % time 158ps typ, 213ps min, 135ps max; typ from 1.63 V to 0.008 V
[POWER_clamp]
|   voltage   I(typ)   I(min)   I(max)
-3.3V     356.5mA    282.7mA    451.6mA
-1.133V   31.76mA    26.3mA     37.93mA
-1.1V     27.55mA    23.03mA    32.62mA
-1.067V   23.89mA    20.19mA    28.02mA
-1.033V   20.23mA    17.34mA    23.41mA
-1V       16.58mA    14.49mA    18.81mA
-900mV    9.688mA    8.484mA    11.19mA
-800mV    7.128mA    5.638mA    8.695mA
-500mV    2.628mA    1.921mA    3.112mA
-300mV    500.7uA    363.4uA    473.7uA
-200mV    74.33uA    66.47uA    49.84uA
-11.55fV  3.93uA     2.512uA    7.043uA
[Pulldown]
|   voltage   I(typ)   I(min)   I(max)
-3.3V     -271.2uA   -186.3uA   -423.5uA
-2.6V     -788.8uA   -400.3uA   -2.959mA
-2.5V     -1.087mA   -480uA     -18.88mA
-2.4V     -1.882mA   -603.6uA   -19.07mA
-2.3V     -13.43mA   -840.1uA   -19.14mA
-2.2V     -13.54mA   -7.71mA    -18.97mA
-500mV    -9.108mA   -7.246mA   -11.33mA
2.2V      41.22mA    30.38mA    52.53mA
3V        51.2mA     33.33mA    68.06mA
3.7V      51.78mA    31.03mA    74.24mA
5V        30.65mA    13.48mA    50.87mA
6.6V      14.41mA    6.604mA    24.31mA
[Pullup]
|   voltage   I(typ)   I(min)   I(max)
-3.3V     9.902mA    4.406mA    15.51mA
-2.6V     11.65mA    6.391mA    16.68mA
-1.4V     10.55mA    8.577mA    13.08mA
-300mV    5.489mA    4.424mA    6.965mA
1.6V      -31.07mA   -24.23mA   -38.95mA
2.8V      -52.79mA   -39.79mA   -66.9mA
3.5V      -64.26mA   -46.15mA   -82.37mA
3.9V      -67.69mA   -43.51mA   -90.28mA
4.2V      -65.25mA   -39.35mA   -91.06mA
5.4V      -51.09mA   -20.64mA   -78.84mA
5.6V      -47.66mA   -17.31mA   -79.91mA
6.6V      -26.86mA   -11.7mA    -58.9mA
[GND_clamp]
|   voltage   I(typ)   I(min)   I(max)
-3.3V     -810.8mA   -746.5mA   -1.068A
-1.1V     -62.29mA   -65.9mA    -80.37mA
-1.033V   -47.47mA   -54.02mA   -56.74mA
-966.7mV  -34.03mA   -42.59mA   -36.13mA
-900mV    -21.98mA   -31.62mA   -18.54mA
-833.3mV  -12.88mA   -21.69mA   -11.1mA
-766.7mV  -6.923mA   -13.08mA   -6.583mA
-700mV    -4.099mA   -5.789mA   -5.001mA
-566.7mV  -1.959mA   -1.696mA   -2.401mA
-500mV    -1.047mA   -899.1uA   -1.26mA
-300mV    -22.08uA   -32.2uA    -20.15uA
3.233V    3.825uA    13.73uA    6.915uA
[Ramp]
| variable   typ   min   max
dV/dt_f   1.031333/0.8048906n  0.8317614/1.573405n   1.213179/0.5171605n
dV/dt_r   1.000662/0.7899555n  0.8274051/1.387543n   1.168984/0.5009531n
R_load = 50
[Rising Waveform]
R_fixture = 50
V_fixture = 3.3
V_fixture_min = 3.135
V_fixture_max = 3.465
|   time   V(typ)   V(min)   V(max)
0s        1.679V     1.814V     1.559V
694ps     1.68V      1.817V     1.569V
746ps     1.679V     1.817V     1.799V
832ps     1.743V     1.816V     2.785V
884ps     2.073V     1.815V     3.09V
954ps     2.678V     1.819V     3.292V
1.076ns   3.125V     2.048V     3.416V
1.196ns   3.232V     2.694V     3.444V
1.284ns   3.258V     2.944V     3.451V
1.704ns   3.287V     3.103V     3.46V
[Rising Waveform]
R_fixture = 50
V_fixture = 0
V_fixture_min = 0
V_fixture_max = 0
|   time   V(typ)   V(min)   V(max)
0s        1.285uV    5.88uV     149nV
958ps     -30.99mV   -2.758mV   11.56mV
1.184ns   25.43mV    -32.67mV   598.3mV
1.524ns   502.2mV    -5.292mV   1.421V
1.75ns    835.5mV    102.1mV    1.674V
1.976ns   1.131V     246.1mV    1.811V
2.598ns   1.517V     678mV      1.894V
3.616ns   1.612V     1.166V     1.902V
4.294ns   1.618V     1.282V     1.904V
5.534ns   1.622V     1.315V     1.905V
[Falling Waveform]
R_fixture = 50
V_fixture = 3.3
V_fixture_min = 3.135
V_fixture_max = 3.465
|   time   V(typ)   V(min)   V(max)
0s        3.3V       3.135V     3.465V
544ps     3.3V       3.135V     3.464V
780ps     3.367V     3.158V     3.564V
1.014ns   3.31V      3.194V     3.256V
1.638ns   2.674V     3.08V      1.838V
1.952ns   2.221V     2.965V     1.617V
2.264ns   1.895V     2.833V     1.571V
2.576ns   1.754V     2.652V     1.563V
4.06ns    1.686V     1.96V      1.558V
7.654ns   1.679V     1.846V     1.556V
[Falling Waveform]
R_fixture = 50
V_fixture = 0
V_fixture_min = 0
V_fixture_max = 0
|   time   V(typ)   V(min)   V(max)
0s        1.626V     1.346V     1.905V
650ps     1.642V     1.346V     1.9V
696ps     1.619V     1.348V     1.731V
744ps     1.522V     1.356V     1.201V
820ps     995.2mV    1.331V     538.1mV
914ps     423.5mV    1.152V     198.1mV
1.022ns   150.9mV    705.7mV    53.91mV
1.178ns   38.83mV    230mV      10.43mV
1.318ns   13.83mV    77.11mV    4.925mV
1.522ns   8.213mV    31.61mV    3.472mV
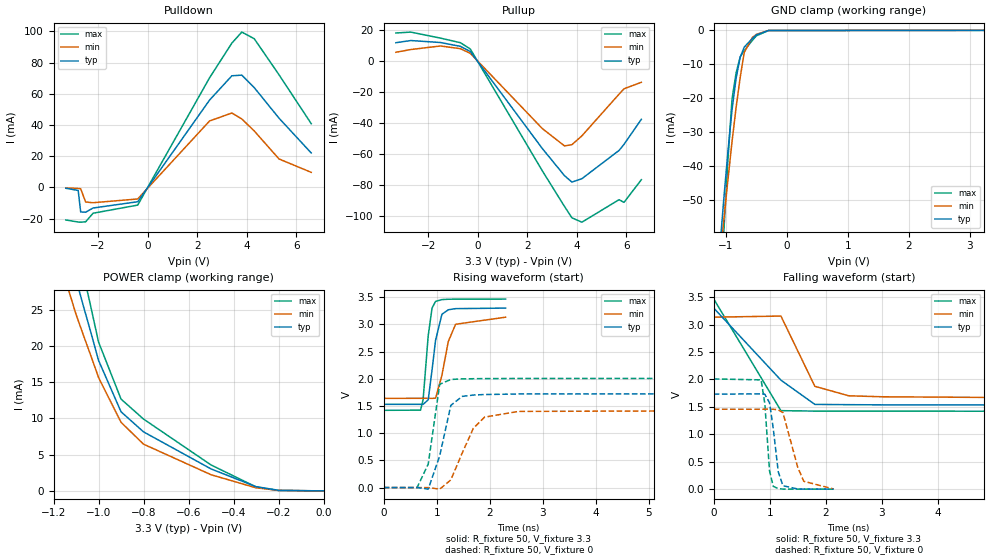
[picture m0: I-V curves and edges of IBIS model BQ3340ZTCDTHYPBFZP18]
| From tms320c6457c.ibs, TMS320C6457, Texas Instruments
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|   Model Cell BQ3340ZTCDTHYPBFZP18
[Model]   BQ3340ZTCDTHYPBFZP18
Model_type   I/O
Polarity   Non-Inverting
Enable   Active-Low
|NORMMAL MODE WEAK PULLUP AND WEAK PULLDOWN OFF +/-5% VDDS
Vinl =  0.8V
Vinh =  2V
Cref =  15pF
Rref =  100.00M
Vref =  0V
Vmeas =  1.65
C_comp   1.574101p   1.494427p   1.661981p
[Model Spec]
Vinl   0.8V   0.8V   0.8V
Vinh   2V   2V   2V
[Temperature Range]   25   125   -40
[Voltage Range]   3.3   3.135   3.465
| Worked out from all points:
|   slope of the pulldown table from 0 to 0.495 V, typ, clamps not added: 42.4 ohm
|   slope of the pullup table from 0 to 0.495 V, typ, clamps not added: 44.7 ohm
|   GND clamp passes 1 mA (typ) near -0.47 V on its own axis
|   POWER clamp passes 1 mA (typ) near -0.34 V on its own axis
|   rising waveform, R_fixture 50, V_fixture 3.3: 20-80 % time 139ps typ, 186ps min, 105ps max; typ from 1.53 V to 3.3 V
|   rising waveform, R_fixture 50, V_fixture 0: 20-80 % time 265ps typ, 434ps min, 188ps max; typ from 0 V to 1.73 V
|   falling waveform, R_fixture 50, V_fixture 3.3: 20-80 % time 1.02ns typ, 424ps min, 724ps max; typ from 3.3 V to 1.53 V
|   falling waveform, R_fixture 50, V_fixture 0: 20-80 % time 118ps typ, 207ps min, 82.7ps max; typ from 1.73 V to 0.001 V
[POWER_clamp]
|   voltage   I(typ)   I(min)   I(max)
-3.3V     362.8mA    288.5mA    459mA
-1.133V   33.51mA    27.72mA    40.02mA
-1.1V     29.22mA    24.38mA    34.62mA
-1.067V   25.49mA    21.48mA    29.93mA
-1.033V   21.76mA    18.57mA    25.25mA
-1V       18.03mA    15.67mA    20.56mA
-900mV    10.93mA    9.48mA     12.68mA
-800mV    8.156mA    6.457mA    9.923mA
-500mV    3.041mA    2.239mA    3.589mA
-300mV    590.8uA    431.5uA    558.3uA
-200mV    88.48uA    79.53uA    58.46uA
-11.55fV  3.931uA    2.517uA    7.043uA
[Pulldown]
|   voltage   I(typ)   I(min)   I(max)
-3.3V     -557.2uA   -337.8uA   -20.9mA
-2.8V     -1.961mA   -678.1uA   -22.19mA
-2.7V     -15.72mA   -873.5uA   -22.31mA
-2.5V     -15.91mA   -9.353mA   -22.07mA
-2.2V     -13.22mA   -9.823mA   -16.57mA
-400mV    -9.186mA   -7.413mA   -11.34mA
2.5V      56.01mA    42.61mA    70.31mA
3.4V      71.58mA    47.71mA    92.56mA
3.8V      71.99mA    43.88mA    99.6mA
4.3V      64.01mA    36.22mA    95.37mA
5.3V      44.41mA    18.24mA    72.25mA
6.6V      22.07mA    9.659mA    40.87mA
[Pullup]
|   voltage   I(typ)   I(min)   I(max)
-3.3V     11.86mA    5.692mA    18.1mA
-2.7V     13.26mA    7.46mA     18.7mA
-1.5V     11.98mA    9.751mA    14.8mA
-700mV    9.519mA    8.006mA    11.86mA
-300mV    6.175mA    5.015mA    7.811mA
2.6V      -56.22mA   -43.4mA    -70.58mA
3.5V      -73.83mA   -54.64mA   -93.65mA
3.8V      -77.95mA   -53.85mA   -101mA
4.2V      -75.78mA   -48.18mA   -103.8mA
5.7V      -57.56mA   -21.3mA    -89.31mA
5.9V      -53.65mA   -17.84mA   -91.01mA
6.6V      -37.5mA    -13.65mA   -76.43mA
[GND_clamp]
|   voltage   I(typ)   I(min)   I(max)
-3.3V     -818mA     -753.1mA   -1.076A
-1.1V     -64.3mA    -67.66mA   -82.73mA
-1.033V   -49.28mA   -55.6mA    -58.88mA
-966.7mV  -35.65mA   -44mA      -38.04mA
-900mV    -23.4mA    -32.85mA   -20.23mA
-833.3mV  -14.11mA   -22.75mA   -12.57mA
-766.7mV  -7.957mA   -13.97mA   -7.822mA
-700mV    -4.939mA   -6.516mA   -6.002mA
-566.7mV  -2.424mA   -2.105mA   -2.951mA
-500mV    -1.336mA   -1.158mA   -1.597mA
-300mV    -30.83uA   -44.99uA   -28.06uA
3.233V    3.807uA    16.05uA    6.911uA
[Ramp]
| variable   typ   min   max
dV/dt_f   1.077007/0.1582239n  0.9079977/0.3568531n   1.240826/98.74215p
dV/dt_r   1.067448/0.2211138n  0.8990992/0.4181066n   1.236347/0.1456147n
R_load = 50
[Rising Waveform]
R_fixture = 50
V_fixture = 3.3
V_fixture_min = 3.135
V_fixture_max = 3.465
|   time   V(typ)   V(min)   V(max)
0s        1.53V      1.64V      1.42V
696ps     1.53V      1.641V     1.423V
744ps     1.529V     1.642V     1.62V
840ps     1.614V     1.641V     2.793V
912ps     2.16V      1.64V      3.299V
978ps     2.705V     1.643V     3.422V
1.098ns   3.185V     2.064V     3.455V
1.218ns   3.268V     2.684V     3.462V
1.356ns   3.289V     3.002V     3.463V
2.298ns   3.299V     3.132V     3.465V
[Rising Waveform]
R_fixture = 50
V_fixture = 0
V_fixture_min = 0
V_fixture_max = 0
|   time   V(typ)   V(min)   V(max)
0s        1.174uV    5.476uV    134.3nV
630ps     184.5uV    144.1uV    207.6uV
840ps     -28.68mV   164uV      431.6mV
1.056ns   581.6mV    -29.38mV   1.898V
1.266ns   1.511V     140.5mV    1.987V
1.482ns   1.676V     638.4mV    1.998V
1.692ns   1.701V     1.092V     2.001V
1.902ns   1.71V      1.295V     2.003V
2.544ns   1.72V      1.4V       2.005V
20.78ns   1.733V     1.453V     2.01V
[Falling Waveform]
R_fixture = 50
V_fixture = 3.3
V_fixture_min = 3.135
V_fixture_max = 3.465
|   time   V(typ)   V(min)   V(max)
0s        3.3V       3.135V     3.465V
1.2ns     1.987V     3.155V     1.431V
1.806ns   1.545V     1.875V     1.423V
2.412ns   1.54V      1.702V     1.422V
3.012ns   1.537V     1.684V     1.422V
6.03ns    1.533V     1.665V     1.42V
13.88ns   1.531V     1.654V     1.419V
59.18ns   1.528V     1.643V     1.419V
[Falling Waveform]
R_fixture = 50
V_fixture = 0
V_fixture_min = 0
V_fixture_max = 0
|   time   V(typ)   V(min)   V(max)
0s        1.732V     1.457V     2.009V
846ps     1.737V     1.457V     1.992V
912ps     1.73V      1.458V     1.561V
996ps     1.576V     1.458V     335.9mV
1.062ns   1.112V     1.457V     52.92mV
1.152ns   316.8mV    1.445V     8.592mV
1.236ns   62.7mV     1.395V     2.199mV
1.5ns     3.091mV    400mV      168.2uV
1.608ns   1.77mV     143.7mV    115uV
2.142ns   701uV      3.236mV    56.03uV
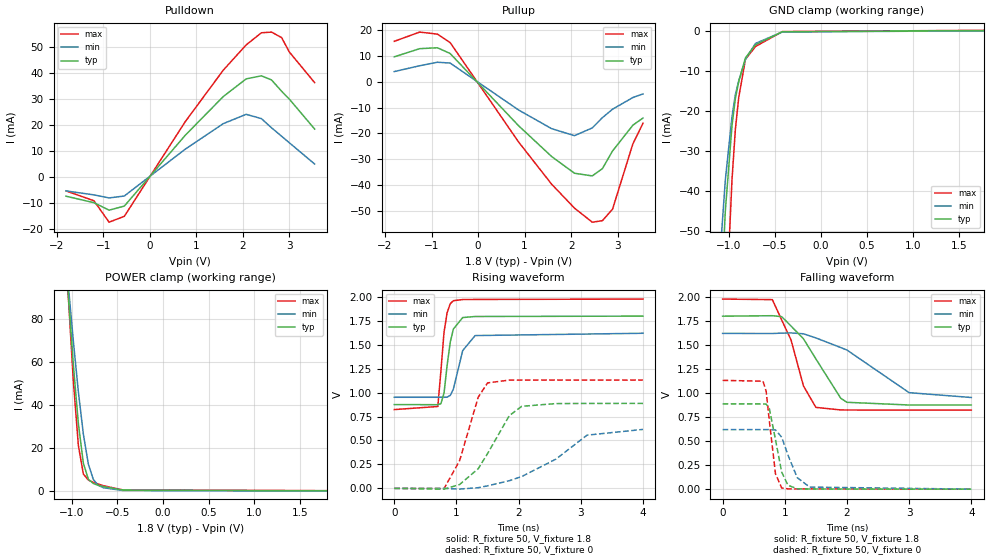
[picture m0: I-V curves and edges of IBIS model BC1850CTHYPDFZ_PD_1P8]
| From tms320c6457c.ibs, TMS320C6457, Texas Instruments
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|   Model Cell BC1850CTHYPDFZ_PD_1P8
[Model]   BC1850CTHYPDFZ_PD_1P8
Model_type   I/O
Polarity   Non-Inverting
Enable   Active-Low
Vinl =  0.63
Vinh =  1.17
Cref =  15.0000pF
Rref =  100.0000M
Vref =  0V
Vmeas =  0.9
C_comp   1.281409p   1.062836p   1.580592p
[Model Spec]
Vinl   0.63   0.567   0.693
Vinh   1.17   1.053   1.287
[Temperature Range]   25   125   -40
[Voltage Range]   1.8   1.62   1.98
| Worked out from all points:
|   slope of the pulldown table from 0 to 0.27 V, typ, clamps not added: 45.7 ohm
|   slope of the pullup table from 0 to 0.27 V, typ, clamps not added: 49.4 ohm
|   GND clamp passes 1 mA (typ) near -0.54 V on its own axis
|   POWER clamp passes 1 mA (typ) near -0.53 V on its own axis
|   rising waveform, R_fixture 50, V_fixture 1.8: 20-80 % time 121ps typ, 165ps min, 101ps max; typ from 0.875 V to 1.8 V
|   rising waveform, R_fixture 50, V_fixture 0: 20-80 % time 498ps typ, 888ps min, 325ps max; typ from 0 V to 0.887 V
|   falling waveform, R_fixture 50, V_fixture 1.8: 20-80 % time 561ps typ, 964ps min, 357ps max; typ from 1.8 V to 0.875 V
|   falling waveform, R_fixture 50, V_fixture 0: 20-80 % time 147ps typ, 220ps min, 117ps max; typ from 0.887 V to 0 V
[POWER_clamp]
|   voltage   I(typ)   I(min)   I(max)
-1.8V     630mA      511.3mA    760.2mA
-1.055V   101.7mA    103.8mA    103.4mA
-1.036V   90.16mA    94.86mA    89.19mA
-981.8mV  58.3mA     69.35mA    50.66mA
-927.3mV  31.21mA    46.06mA    21.11mA
-872.7mV  12.91mA    26.44mA    7.906mA
-818.2mV  5.483mA    12.55mA    5.094mA
-763.6mV  3.485mA    5.369mA    4.062mA
-709.1mV  2.671mA    2.61mA     3.233mA
-654.5mV  2.073mA    1.538mA    2.479mA
-436.4mV  436.3uA    214.5uA    475.8uA
1.8V      92.33uA    43.86uA    171.9uA
[Pulldown]
|   voltage   I(typ)   I(min)   I(max)
-1.8V     -7.221mA   -5.188mA   -5.193mA
-1.2V     -9.719mA   -6.718mA   -8.96mA
-872.7mV  -12.6mA    -7.896mA   -17.22mA
-545.5mV  -11.02mA   -7.144mA   -14.95mA
763.6mV   16.19mA    10.86mA    21.42mA
1.582V    31.1mA     20.68mA    41.25mA
2.073V    37.88mA    24.25mA    50.93mA
2.4V      39.06mA    22.61mA    55.6mA
2.618V    37.47mA    19.08mA    55.87mA
2.836V    33.11mA    15.81mA    53.74mA
3V        30.12mA    13.33mA    48.23mA
3.545V    18.59mA    5.142mA    36.43mA
[Pullup]
|   voltage   I(typ)   I(min)   I(max)
-1.8V     9.587mA    3.896mA    15.57mA
-1.255V   12.73mA    6.137mA    19.13mA
-872.7mV  13.08mA    7.494mA    18.34mA
-600mV    10.87mA    7.175mA    15.09mA
872.7mV   -17.04mA   -10.95mA   -23.32mA
1.582V    -28.9mA    -18.15mA   -39.58mA
2.073V    -35.35mA   -20.84mA   -48.81mA
2.455V    -36.38mA   -17.86mA   -54.24mA
2.673V    -33.57mA   -13.9mA    -53.65mA
2.891V    -26.75mA   -10.62mA   -49.2mA
3.327V    -16.82mA   -6.13mA    -24.05mA
3.545V    -14.03mA   -4.729mA   -16.07mA
[GND_clamp]
|   voltage   I(typ)   I(min)   I(max)
-1.8V     -611mA     -423mA     -952.5mA
-1.145V   -105.8mA   -77.65mA   -174.4mA
-1.109V   -83.49mA   -62.95mA   -137.9mA
-1.073V   -63.24mA   -49.51mA   -104.5mA
-1.036V   -45.06mA   -37.35mA   -74.13mA
-963.6mV  -23.66mA   -21.45mA   -37.2mA
-927.3mV  -16.92mA   -15.95mA   -24.68mA
-890.9mV  -12.74mA   -12.47mA   -16.69mA
-818.2mV  -6.749mA   -7.099mA   -7.115mA
-709.1mV  -3.431mA   -3.112mA   -3.887mA
-418.2mV  -186.2uA   -244.2uA   -149uA
1.764V    92.28uA    44.41uA    171.2uA
[Ramp]
| variable   typ   min   max
dV/dt_f   0.557709/0.5695101n  0.4025171/0.9783267n  0.6966706/0.3579203n
dV/dt_r  0.5377679/0.5059881n  0.3737538/0.9045049n  0.6855358/0.3297064n
R_load = 50
[Rising Waveform]
R_fixture = 50
V_fixture = 1.8
V_fixture_min = 1.62
V_fixture_max = 1.98
| time   V(typ)   V(min)   V(max)
|   time   V(typ)   V(min)   V(max)
0s        874.6mV    951mV      822.3mV
700ps     873.4mV    951mV      854.7mV
750ps     884.3mV    951mV      1.227V
800ps     995.1mV    951mV      1.63V
850ps     1.285V     951.9mV    1.835V
900ps     1.526V     970.5mV    1.927V
950ps     1.663V     1.036V     1.959V
1.1ns     1.783V     1.438V     1.971V
1.3ns     1.794V     1.595V     1.972V
4ns       1.798V     1.619V     1.976V
[Rising Waveform]
R_fixture = 50
V_fixture = 0
V_fixture_min = 0
V_fixture_max = 0
| time   V(typ)   V(min)   V(max)
|   time   V(typ)   V(min)   V(max)
0s        527.5nV    471.9nV    628.5nV
800ps     -8.234mV   -27.58uV   -2.003mV
1.05ns    39.93mV    -7.275mV   287.9mV
1.35ns    205.2mV    7.122mV    952.3mV
1.5ns     363.1mV    26.46mV    1.101V
1.85ns    759.2mV    79.93mV    1.13V
2.05ns    856.7mV    123.7mV    1.131V
2.6ns     885.1mV    305.4mV    1.131V
3.1ns     886.5mV    555.6mV    1.131V
4ns       886.7mV    615.6mV    1.131V
[Falling Waveform]
R_fixture = 50
V_fixture = 1.8
V_fixture_min = 1.62
V_fixture_max = 1.98
| time   V(typ)   V(min)   V(max)
|   time   V(typ)   V(min)   V(max)
0s        1.798V     1.619V     1.976V
800ps     1.803V     1.618V     1.97V
950ps     1.793V     1.622V     1.758V
1.1ns     1.696V     1.624V     1.552V
1.3ns     1.563V     1.615V     1.073V
1.5ns     1.354V     1.572V     850.1mV
1.9ns     945mV      1.472V     823.3mV
2ns       902.9mV    1.446V     822.8mV
3ns       874.8mV    1.003V     822.3mV
4ns       874.6mV    952.9mV    822.3mV
[Falling Waveform]
R_fixture = 50
V_fixture = 0
V_fixture_min = 0
V_fixture_max = 0
| time   V(typ)   V(min)   V(max)
|   time   V(typ)   V(min)   V(max)
0s        886.7mV    619.2mV    1.131V
650ps     886.5mV    619.2mV    1.122V
700ps     884.2mV    619.2mV    1.017V
750ps     841.4mV    619.2mV    717.6mV
850ps     515.4mV    615.7mV    160mV
950ps     177.7mV    540.6mV    12.74mV
1.05ns    41.18mV    356mV      3.385mV
1.2ns     3.612mV    119.6mV    2.239mV
1.4ns     1.895mV    21.55mV    3.457mV
4ns       804.7nV    156uV      632.9nV
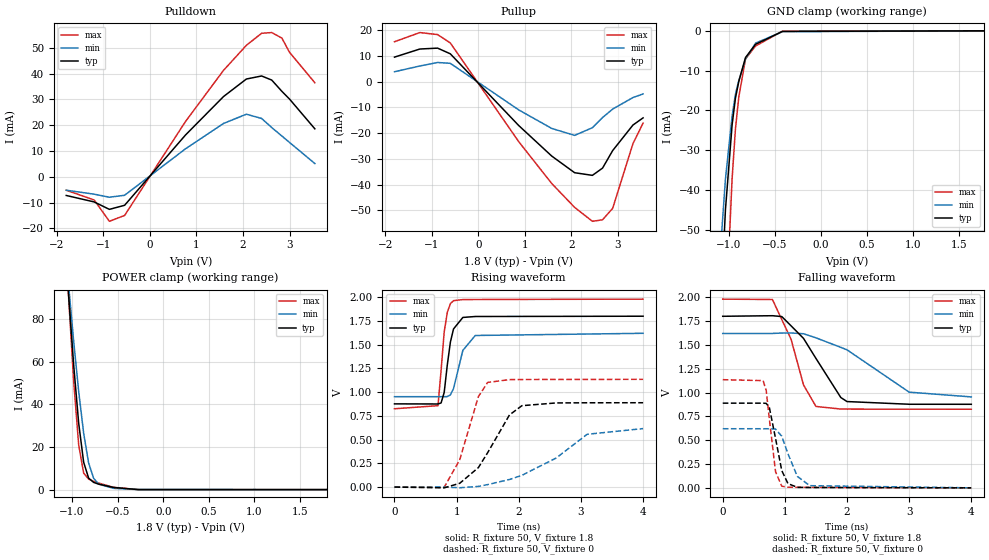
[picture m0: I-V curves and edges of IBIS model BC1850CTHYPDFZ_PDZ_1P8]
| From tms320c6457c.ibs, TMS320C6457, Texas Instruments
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|   Model Cell 1850CTHYPDFZ_PDZ_1P8
[Model]   BC1850CTHYPDFZ_PDZ_1P8
Model_type   I/O
Polarity   Non-Inverting
Enable   Active-Low
Vinl =  0.63
Vinh =  1.17
Cref =  15.0000pF
Rref =  100.0000M
Vref =  0V
Vmeas =  0.9
C_comp   1.281409p   1.062836p   1.580592p
[Model Spec]
Vinl   0.63   0.567   0.693
Vinh   1.17   1.053   1.287
[Temperature Range]   25   125   -40
[Voltage Range]   1.8   1.62   1.98
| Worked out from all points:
|   slope of the pulldown table from 0 to 0.27 V, typ, clamps not added: 45.7 ohm
|   slope of the pullup table from 0 to 0.27 V, typ, clamps not added: 49.4 ohm
|   GND clamp passes 1 mA (typ) near -0.54 V on its own axis
|   POWER clamp passes 1 mA (typ) near -0.54 V on its own axis
|   rising waveform, R_fixture 50, V_fixture 1.8: 20-80 % time 121ps typ, 165ps min, 101ps max; typ from 0.877 V to 1.8 V
|   rising waveform, R_fixture 50, V_fixture 0: 20-80 % time 499ps typ, 888ps min, 325ps max; typ from 0 V to 0.888 V
|   falling waveform, R_fixture 50, V_fixture 1.8: 20-80 % time 560ps typ, 962ps min, 357ps max; typ from 1.8 V to 0.877 V
|   falling waveform, R_fixture 50, V_fixture 0: 20-80 % time 149ps typ, 220ps min, 118ps max; typ from 0.889 V to 0 V
[POWER_clamp]
|   voltage   I(typ)   I(min)   I(max)
-1.8V     629.9mA    511.3mA    760mA
-1.055V   101.6mA    103.8mA    103.2mA
-1.036V   90.07mA    94.82mA    89.03mA
-981.8mV  58.22mA    69.31mA    50.5mA
-927.3mV  31.12mA    46.02mA    20.95mA
-872.7mV  12.82mA    26.4mA     7.735mA
-818.2mV  5.391mA    12.51mA    4.922mA
-763.6mV  3.392mA    5.326mA    3.89mA
-709.1mV  2.578mA    2.566mA    3.061mA
-545.5mV  1.007mA    597.2uA    1.066mA
-272.7mV  13.66uA    7.798uA    6.98uA
1.8V      220.4nA    202.9nA    351.6nA
[Pulldown]
|   voltage   I(typ)   I(min)   I(max)
-1.8V     -7.221mA   -5.188mA   -5.193mA
-1.2V     -9.719mA   -6.718mA   -8.96mA
-872.7mV  -12.6mA    -7.896mA   -17.22mA
-545.5mV  -11.02mA   -7.144mA   -14.95mA
763.6mV   16.19mA    10.86mA    21.42mA
1.582V    31.1mA     20.68mA    41.25mA
2.073V    37.88mA    24.25mA    50.93mA
2.4V      39.06mA    22.61mA    55.6mA
2.618V    37.47mA    19.08mA    55.87mA
2.836V    33.11mA    15.81mA    53.74mA
3V        30.12mA    13.33mA    48.23mA
3.545V    18.59mA    5.141mA    36.43mA
[Pullup]
|   voltage   I(typ)   I(min)   I(max)
-1.8V     9.587mA    3.896mA    15.57mA
-1.255V   12.73mA    6.137mA    19.13mA
-872.7mV  13.08mA    7.494mA    18.34mA
-600mV    10.87mA    7.175mA    15.09mA
872.7mV   -17.04mA   -10.95mA   -23.32mA
1.582V    -28.9mA    -18.15mA   -39.58mA
2.073V    -35.35mA   -20.84mA   -48.82mA
2.455V    -36.38mA   -17.86mA   -54.24mA
2.673V    -33.57mA   -13.9mA    -53.65mA
2.891V    -26.75mA   -10.62mA   -49.2mA
3.327V    -16.82mA   -6.13mA    -24.05mA
3.545V    -14.03mA   -4.729mA   -16.07mA
[GND_clamp]
|   voltage   I(typ)   I(min)   I(max)
-1.8V     -611mA     -423mA     -952.5mA
-1.145V   -105.8mA   -77.65mA   -174.4mA
-1.109V   -83.48mA   -62.94mA   -137.9mA
-1.073V   -63.23mA   -49.51mA   -104.5mA
-1.036V   -45.05mA   -37.34mA   -74.11mA
-963.6mV  -23.64mA   -21.44mA   -37.17mA
-927.3mV  -16.9mA    -15.94mA   -24.64mA
-890.9mV  -12.72mA   -12.46mA   -16.64mA
-818.2mV  -6.714mA   -7.087mA   -7.047mA
-709.1mV  -3.387mA   -3.093mA   -3.814mA
-418.2mV  -145.8uA   -222.8uA   -82.7uA
1.764V    207nA      672.9nA    274.1nA
[Ramp]
| variable   typ   min   max
dV/dt_f  0.5582307/0.568567n   0.4027497/0.9766949n  0.6977698/0.3576327n
dV/dt_r  0.5388744/0.5062068n  0.3741033/0.9046042n  0.6875178/0.3298689n
R_load = 50
[Rising Waveform]
R_fixture = 50
V_fixture = 1.8
V_fixture_min = 1.62
V_fixture_max = 1.98
| time   V(typ)   V(min)   V(max)
|   time   V(typ)   V(min)   V(max)
0s        876.6mV    952.2mV    825mV
700ps     875.3mV    952.2mV    857.7mV
750ps     886.3mV    952.3mV    1.231V
800ps     997.6mV    952.3mV    1.635V
850ps     1.288V     953.1mV    1.841V
900ps     1.529V     971.8mV    1.933V
950ps     1.666V     1.038V     1.964V
1.1ns     1.787V     1.44V      1.975V
1.3ns     1.797V     1.597V     1.976V
4ns       1.8V       1.62V      1.98V
[Rising Waveform]
R_fixture = 50
V_fixture = 0
V_fixture_min = 0
V_fixture_max = 0
| time   V(typ)   V(min)   V(max)
|   time   V(typ)   V(min)   V(max)
0s        526.1nV    471.7nV    624.6nV
800ps     -8.237mV   -27.53uV   -2.013mV
1.05ns    39.94mV    -7.277mV   288.2mV
1.35ns    205.4mV    7.121mV    953.5mV
1.5ns     363.4mV    26.47mV    1.103V
1.85ns    759.9mV    79.96mV    1.132V
2.05ns    857.5mV    123.8mV    1.133V
2.6ns     886.4mV    305.6mV    1.134V
3.1ns     888.1mV    556mV      1.134V
4ns       888.5mV    616.2mV    1.135V
[Falling Waveform]
R_fixture = 50
V_fixture = 1.8
V_fixture_min = 1.62
V_fixture_max = 1.98
| time   V(typ)   V(min)   V(max)
|   time   V(typ)   V(min)   V(max)
0s        1.8V       1.62V      1.98V
800ps     1.806V     1.62V      1.976V
950ps     1.797V     1.624V     1.766V
1.1ns     1.7V       1.625V     1.559V
1.3ns     1.568V     1.617V     1.08V
1.5ns     1.358V     1.574V     854.1mV
1.9ns     947.8mV    1.474V     826.9mV
2ns       905.4mV    1.448V     826.3mV
3ns       877.1mV    1.004V     825.2mV
4ns       876.7mV    954.2mV    825mV
[Falling Waveform]
R_fixture = 50
V_fixture = 0
V_fixture_min = 0
V_fixture_max = 0
| time   V(typ)   V(min)   V(max)
|   time   V(typ)   V(min)   V(max)
0s        888.7mV    620.2mV    1.135V
650ps     888.5mV    620.2mV    1.125V
700ps     886.2mV    620.2mV    1.021V
750ps     843.6mV    620.2mV    723.7mV
850ps     518.5mV    616.7mV    168.1mV
950ps     181.1mV    541.8mV    17.12mV
1.05ns    44.2mV     357.4mV    7.003mV
1.2ns     5.888mV    121.1mV    4.911mV
1.4ns     3.787mV    22.89mV    5.267mV
4ns       45.93uV    323.4uV    5.908uV
